VERSION 5.8 ;
BUSBITCHARS "[]" ;
DIVIDERCHAR "/" ;
UNITS
    DATABASE MICRONS 1000 ;
END UNITS

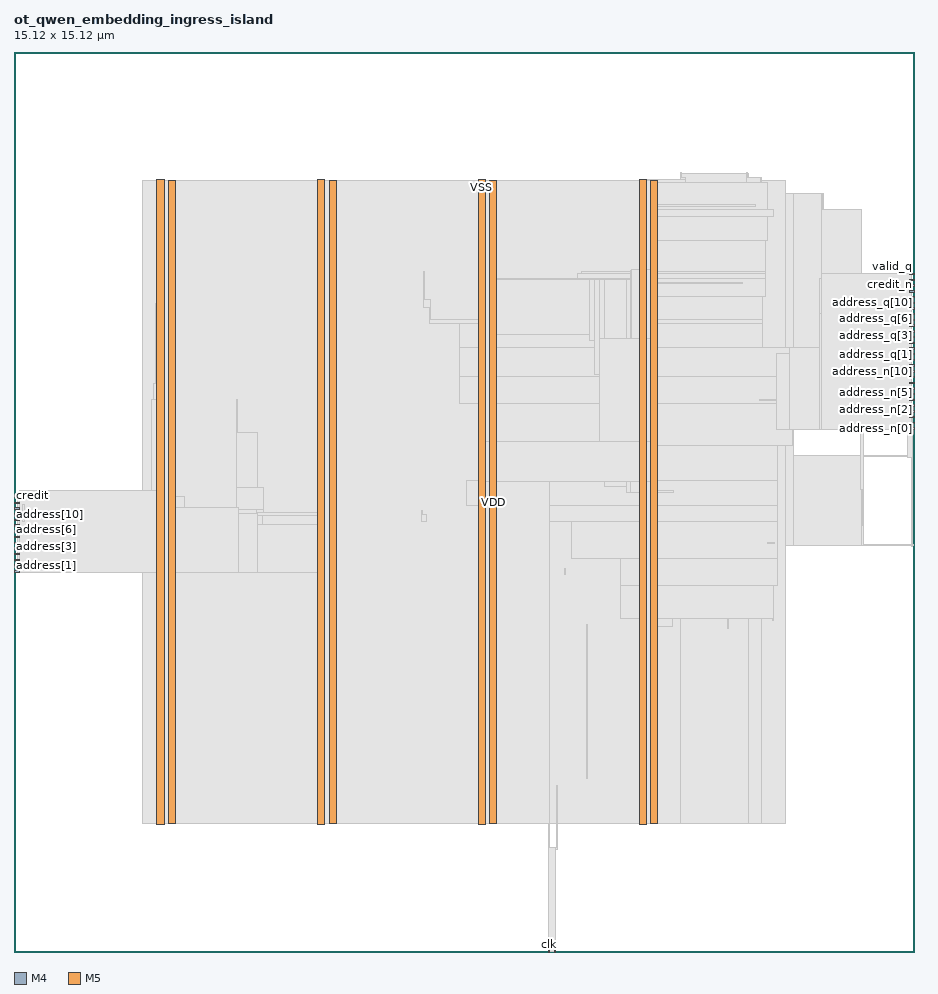
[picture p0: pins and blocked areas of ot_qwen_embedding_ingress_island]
MACRO ot_qwen_embedding_ingress_island
  FOREIGN ot_qwen_embedding_ingress_island 0 0 ;
  CLASS BLOCK ;
  SIZE 15.12 BY 15.12 ;
  PIN address[0]
    DIRECTION INPUT ;
    USE SIGNAL ;
    PORT
      LAYER M4 ;
        RECT  0 6.384 0.084 6.408 ;
    END
  END address[0]
  PIN address[10]
    DIRECTION INPUT ;
    USE SIGNAL ;
    PORT
      LAYER M4 ;
        RECT  0 7.344 0.084 7.368 ;
    END
  END address[10]
  PIN address[11]
    DIRECTION INPUT ;
    USE SIGNAL ;
    PORT
      LAYER M4 ;
        RECT  0 7.44 0.084 7.464 ;
    END
  END address[11]
  PIN address[1]
    DIRECTION INPUT ;
    USE SIGNAL ;
    PORT
      LAYER M4 ;
        RECT  0 6.48 0.084 6.504 ;
    END
  END address[1]
  PIN address[2]
    DIRECTION INPUT ;
    USE SIGNAL ;
    PORT
      LAYER M4 ;
        RECT  0 6.576 0.084 6.6 ;
    END
  END address[2]
  PIN address[3]
    DIRECTION INPUT ;
    USE SIGNAL ;
    PORT
      LAYER M4 ;
        RECT  0 6.672 0.084 6.696 ;
    END
  END address[3]
  PIN address[4]
    DIRECTION INPUT ;
    USE SIGNAL ;
    PORT
      LAYER M4 ;
        RECT  0 6.768 0.084 6.792 ;
    END
  END address[4]
  PIN address[5]
    DIRECTION INPUT ;
    USE SIGNAL ;
    PORT
      LAYER M4 ;
        RECT  0 6.864 0.084 6.888 ;
    END
  END address[5]
  PIN address[6]
    DIRECTION INPUT ;
    USE SIGNAL ;
    PORT
      LAYER M4 ;
        RECT  0 6.96 0.084 6.984 ;
    END
  END address[6]
  PIN address[7]
    DIRECTION INPUT ;
    USE SIGNAL ;
    PORT
      LAYER M4 ;
        RECT  0 7.056 0.084 7.08 ;
    END
  END address[7]
  PIN address[8]
    DIRECTION INPUT ;
    USE SIGNAL ;
    PORT
      LAYER M4 ;
        RECT  0 7.152 0.084 7.176 ;
    END
  END address[8]
  PIN address[9]
    DIRECTION INPUT ;
    USE SIGNAL ;
    PORT
      LAYER M4 ;
        RECT  0 7.248 0.084 7.272 ;
    END
  END address[9]
  PIN address_n[0]
    DIRECTION OUTPUT ;
    USE SIGNAL ;
    PORT
      LAYER M4 ;
        RECT  15.036 8.784 15.12 8.808 ;
    END
  END address_n[0]
  PIN address_n[10]
    DIRECTION OUTPUT ;
    USE SIGNAL ;
    PORT
      LAYER M4 ;
        RECT  15.036 9.744 15.12 9.768 ;
    END
  END address_n[10]
  PIN address_n[11]
    DIRECTION OUTPUT ;
    USE SIGNAL ;
    PORT
      LAYER M4 ;
        RECT  15.036 9.84 15.12 9.864 ;
    END
  END address_n[11]
  PIN address_n[1]
    DIRECTION OUTPUT ;
    USE SIGNAL ;
    PORT
      LAYER M4 ;
        RECT  15.036 8.88 15.12 8.904 ;
    END
  END address_n[1]
  PIN address_n[2]
    DIRECTION OUTPUT ;
    USE SIGNAL ;
    PORT
      LAYER M4 ;
        RECT  15.036 8.976 15.12 9 ;
    END
  END address_n[2]
  PIN address_n[3]
    DIRECTION OUTPUT ;
    USE SIGNAL ;
    PORT
      LAYER M4 ;
        RECT  15.036 9.072 15.12 9.096 ;
    END
  END address_n[3]
  PIN address_n[4]
    DIRECTION OUTPUT ;
    USE SIGNAL ;
    PORT
      LAYER M4 ;
        RECT  15.036 9.168 15.12 9.192 ;
    END
  END address_n[4]
  PIN address_n[5]
    DIRECTION OUTPUT ;
    USE SIGNAL ;
    PORT
      LAYER M4 ;
        RECT  15.036 9.264 15.12 9.288 ;
    END
  END address_n[5]
  PIN address_n[6]
    DIRECTION OUTPUT ;
    USE SIGNAL ;
    PORT
      LAYER M4 ;
        RECT  15.036 9.36 15.12 9.384 ;
    END
  END address_n[6]
  PIN address_n[7]
    DIRECTION OUTPUT ;
    USE SIGNAL ;
    PORT
      LAYER M4 ;
        RECT  15.036 9.456 15.12 9.48 ;
    END
  END address_n[7]
  PIN address_n[8]
    DIRECTION OUTPUT ;
    USE SIGNAL ;
    PORT
      LAYER M4 ;
        RECT  15.036 9.552 15.12 9.576 ;
    END
  END address_n[8]
  PIN address_n[9]
    DIRECTION OUTPUT ;
    USE SIGNAL ;
    PORT
      LAYER M4 ;
        RECT  15.036 9.648 15.12 9.672 ;
    END
  END address_n[9]
  PIN address_q[0]
    DIRECTION OUTPUT ;
    USE SIGNAL ;
    PORT
      LAYER M4 ;
        RECT  15.036 9.936 15.12 9.96 ;
    END
  END address_q[0]
  PIN address_q[10]
    DIRECTION OUTPUT ;
    USE SIGNAL ;
    PORT
      LAYER M4 ;
        RECT  15.036 10.896 15.12 10.92 ;
    END
  END address_q[10]
  PIN address_q[11]
    DIRECTION OUTPUT ;
    USE SIGNAL ;
    PORT
      LAYER M4 ;
        RECT  15.036 10.992 15.12 11.016 ;
    END
  END address_q[11]
  PIN address_q[1]
    DIRECTION OUTPUT ;
    USE SIGNAL ;
    PORT
      LAYER M4 ;
        RECT  15.036 10.032 15.12 10.056 ;
    END
  END address_q[1]
  PIN address_q[2]
    DIRECTION OUTPUT ;
    USE SIGNAL ;
    PORT
      LAYER M4 ;
        RECT  15.036 10.128 15.12 10.152 ;
    END
  END address_q[2]
  PIN address_q[3]
    DIRECTION OUTPUT ;
    USE SIGNAL ;
    PORT
      LAYER M4 ;
        RECT  15.036 10.224 15.12 10.248 ;
    END
  END address_q[3]
  PIN address_q[4]
    DIRECTION OUTPUT ;
    USE SIGNAL ;
    PORT
      LAYER M4 ;
        RECT  15.036 10.32 15.12 10.344 ;
    END
  END address_q[4]
  PIN address_q[5]
    DIRECTION OUTPUT ;
    USE SIGNAL ;
    PORT
      LAYER M4 ;
        RECT  15.036 10.416 15.12 10.44 ;
    END
  END address_q[5]
  PIN address_q[6]
    DIRECTION OUTPUT ;
    USE SIGNAL ;
    PORT
      LAYER M4 ;
        RECT  15.036 10.512 15.12 10.536 ;
    END
  END address_q[6]
  PIN address_q[7]
    DIRECTION OUTPUT ;
    USE SIGNAL ;
    PORT
      LAYER M4 ;
        RECT  15.036 10.608 15.12 10.632 ;
    END
  END address_q[7]
  PIN address_q[8]
    DIRECTION OUTPUT ;
    USE SIGNAL ;
    PORT
      LAYER M4 ;
        RECT  15.036 10.704 15.12 10.728 ;
    END
  END address_q[8]
  PIN address_q[9]
    DIRECTION OUTPUT ;
    USE SIGNAL ;
    PORT
      LAYER M4 ;
        RECT  15.036 10.8 15.12 10.824 ;
    END
  END address_q[9]
  PIN clk
    DIRECTION INPUT ;
    USE SIGNAL ;
    PORT
      LAYER M5 ;
        RECT  8.976 0 9 0.084 ;
    END
  END clk
  PIN credit
    DIRECTION INPUT ;
    USE SIGNAL ;
    PORT
      LAYER M4 ;
        RECT  0 7.536 0.084 7.56 ;
    END
  END credit
  PIN credit_n
    DIRECTION OUTPUT ;
    USE SIGNAL ;
    PORT
      LAYER M4 ;
        RECT  15.036 11.088 15.12 11.112 ;
    END
  END credit_n
  PIN credit_q
    DIRECTION OUTPUT ;
    USE SIGNAL ;
    PORT
      LAYER M4 ;
        RECT  15.036 11.184 15.12 11.208 ;
    END
  END credit_q
  PIN rst_n
    DIRECTION INPUT ;
    USE SIGNAL ;
    PORT
      LAYER M5 ;
        RECT  9.072 0 9.096 0.084 ;
    END
  END rst_n
  PIN valid
    DIRECTION INPUT ;
    USE SIGNAL ;
    PORT
      LAYER M4 ;
        RECT  0 7.632 0.084 7.656 ;
    END
  END valid
  PIN valid_n
    DIRECTION OUTPUT ;
    USE SIGNAL ;
    PORT
      LAYER M4 ;
        RECT  15.036 11.28 15.12 11.304 ;
    END
  END valid_n
  PIN valid_q
    DIRECTION OUTPUT ;
    USE SIGNAL ;
    PORT
      LAYER M4 ;
        RECT  15.036 11.376 15.12 11.4 ;
    END
  END valid_q
  PIN VDD
    DIRECTION INOUT ;
    USE POWER ;
    PORT
      LAYER M5 ;
        RECT  10.692 2.151 10.812 12.969 ;
        RECT  7.992 2.151 8.112 12.969 ;
        RECT  5.292 2.151 5.412 12.969 ;
        RECT  2.592 2.151 2.712 12.969 ;
    END
  END VDD
  PIN VSS
    DIRECTION INOUT ;
    USE GROUND ;
    PORT
      LAYER M5 ;
        RECT  10.5 2.137 10.62 12.983 ;
        RECT  7.8 2.137 7.92 12.983 ;
        RECT  5.1 2.137 5.22 12.983 ;
        RECT  2.4 2.137 2.52 12.983 ;
    END
  END VSS
  OBS
    LAYER RVTN ;
     RECT  2.16 2.16 12.96 2.295 ;
     RECT  2.16 2.565 12.96 2.835 ;
     RECT  2.16 3.105 12.96 3.375 ;
     RECT  2.16 3.645 12.96 3.915 ;
     RECT  2.16 4.185 12.96 4.455 ;
     RECT  2.16 4.725 12.96 4.995 ;
     RECT  2.16 5.265 12.96 5.535 ;
     RECT  2.16 5.805 12.96 6.075 ;
     RECT  2.16 6.345 12.96 6.615 ;
     RECT  2.16 6.885 12.96 7.155 ;
     RECT  2.16 7.425 12.96 7.695 ;
     RECT  2.16 7.965 12.96 8.235 ;
     RECT  2.16 8.505 12.96 8.775 ;
     RECT  2.16 9.045 12.96 9.315 ;
     RECT  2.16 9.585 12.96 9.855 ;
     RECT  2.16 10.125 12.96 10.395 ;
     RECT  2.16 10.665 12.96 10.935 ;
     RECT  2.16 11.205 12.96 11.475 ;
     RECT  2.16 11.745 12.96 12.015 ;
     RECT  2.16 12.285 12.96 12.555 ;
     RECT  2.16 12.825 12.96 12.96 ;
    LAYER RVTP ;
     RECT  2.16 2.295 12.96 2.565 ;
     RECT  2.16 2.835 12.96 3.105 ;
     RECT  2.16 3.375 12.96 3.645 ;
     RECT  2.16 3.915 12.96 4.185 ;
     RECT  2.16 4.455 12.96 4.725 ;
     RECT  2.16 4.995 12.96 5.265 ;
     RECT  2.16 5.535 12.96 5.805 ;
     RECT  2.16 6.075 12.96 6.345 ;
     RECT  2.16 6.615 12.96 6.885 ;
     RECT  2.16 7.155 12.96 7.425 ;
     RECT  2.16 7.695 12.96 7.965 ;
     RECT  2.16 8.235 12.96 8.505 ;
     RECT  2.16 8.775 12.96 9.045 ;
     RECT  2.16 9.315 12.96 9.585 ;
     RECT  2.16 9.855 12.96 10.125 ;
     RECT  2.16 10.395 12.96 10.665 ;
     RECT  2.16 10.935 12.96 11.205 ;
     RECT  2.16 11.475 12.96 11.745 ;
     RECT  2.16 12.015 12.96 12.285 ;
     RECT  2.16 12.555 12.96 12.825 ;
    LAYER M1 ;
     RECT  2.16 2.151 12.96 12.969 ;
    LAYER M2 ;
     RECT  2.16 2.151 11.191 12.969 ;
     RECT  11.191 2.151 12.335 13.086 ;
     RECT  12.335 2.151 12.551 13.014 ;
     RECT  12.551 2.151 12.96 12.969 ;
     RECT  12.96 6.822 13.091 12.744 ;
     RECT  13.091 9.09 13.595 12.744 ;
     RECT  13.595 9.09 14.171 12.474 ;
     RECT  14.171 9.09 14.207 10.926 ;
     RECT  14.171 12.186 14.207 12.474 ;
     RECT  13.091 6.822 14.243 8.334 ;
     RECT  14.207 9.36 14.243 10.926 ;
     RECT  14.207 12.456 14.243 12.474 ;
     RECT  14.243 6.822 14.279 7.182 ;
     RECT  14.243 8.316 15.035 8.334 ;
     RECT  14.279 6.822 15.107 6.84 ;
     RECT  15.007 9.171 15.107 9.189 ;
    LAYER M3 ;
     RECT  2.415 2.143 2.505 2.413 ;
     RECT  5.115 2.143 5.205 2.413 ;
     RECT  7.815 2.143 7.905 2.413 ;
     RECT  10.515 2.143 10.605 2.413 ;
     RECT  9.108 1.723 9.126 2.795 ;
     RECT  10.515 2.413 10.797 5.467 ;
     RECT  9.612 2.911 9.63 5.495 ;
     RECT  10.515 5.467 11.07 5.611 ;
     RECT  11.988 5.431 12.006 5.611 ;
     RECT  12.744 5.575 12.762 5.611 ;
     RECT  10.188 5.611 12.762 6.151 ;
     RECT  5.115 2.413 5.397 6.379 ;
     RECT  9.252 6.349 9.27 6.449 ;
     RECT  2.415 2.413 2.697 6.475 ;
     RECT  4.68 6.379 5.397 6.571 ;
     RECT  10.188 6.151 12.834 6.619 ;
     RECT  4.572 6.571 5.397 6.667 ;
     RECT  7.815 2.413 8.097 7.159 ;
     RECT  7.815 7.159 8.298 7.231 ;
     RECT  9.36 6.619 12.834 7.231 ;
     RECT  2.304 6.475 2.697 7.321 ;
     RECT  4.176 6.667 5.397 7.339 ;
     RECT  6.84 7.231 6.93 7.349 ;
     RECT  4.068 7.339 5.397 7.385 ;
     RECT  6.84 7.349 6.858 7.421 ;
     RECT  4.068 7.385 4.194 7.435 ;
     RECT  7.815 7.231 12.834 7.501 ;
     RECT  0.324 7.531 0.342 7.627 ;
     RECT  2.304 7.321 2.862 7.655 ;
     RECT  0.108 7.627 0.342 7.661 ;
     RECT  0.108 7.661 0.126 7.757 ;
     RECT  14.256 7.159 14.274 7.771 ;
     RECT  3.744 7.435 4.194 7.799 ;
     RECT  7.596 7.501 12.834 7.925 ;
     RECT  15.084 6.817 15.102 8.311 ;
     RECT  7.815 7.925 12.834 8.509 ;
     RECT  3.744 7.799 4.086 8.735 ;
     RECT  14.22 7.771 14.274 9.005 ;
     RECT  14.22 9.005 14.238 9.085 ;
     RECT  15.012 8.311 15.102 9.194 ;
     RECT  15.012 9.194 15.03 9.197 ;
     RECT  7.815 8.509 13.086 9.211 ;
     RECT  2.304 7.655 2.697 9.275 ;
     RECT  3.744 8.735 3.762 9.275 ;
     RECT  2.34 9.275 2.697 9.545 ;
     RECT  7.488 9.211 13.086 9.661 ;
     RECT  14.184 9.085 14.238 9.661 ;
     RECT  7.488 9.661 14.238 10.157 ;
     RECT  7.488 10.157 12.582 10.561 ;
     RECT  6.984 10.561 12.582 10.625 ;
     RECT  6.984 10.625 7.002 10.831 ;
     RECT  2.376 9.545 2.697 10.895 ;
     RECT  6.876 10.831 7.002 10.967 ;
     RECT  7.815 10.625 12.582 11.011 ;
     RECT  13.536 10.157 14.238 11.309 ;
     RECT  7.815 11.011 12.618 11.315 ;
     RECT  9.468 11.315 12.618 11.399 ;
     RECT  6.876 10.967 6.894 11.435 ;
     RECT  9.54 11.399 12.618 11.435 ;
     RECT  10.515 11.435 12.618 11.947 ;
     RECT  10.515 11.947 12.654 12.361 ;
     RECT  10.515 12.361 12.762 12.479 ;
     RECT  13.572 11.309 14.238 12.479 ;
     RECT  2.415 10.895 2.697 12.707 ;
     RECT  5.115 7.385 5.397 12.707 ;
     RECT  7.815 11.315 8.097 12.707 ;
     RECT  13.572 12.479 13.59 12.749 ;
     RECT  10.515 12.479 12.654 12.929 ;
     RECT  2.415 12.707 2.505 12.977 ;
     RECT  5.115 12.707 5.205 12.977 ;
     RECT  7.815 12.707 7.905 12.977 ;
     RECT  10.515 12.929 11.286 12.977 ;
     RECT  11.196 12.977 11.286 13.019 ;
     RECT  12.312 12.929 12.546 13.019 ;
     RECT  11.196 13.019 11.214 13.091 ;
     RECT  12.312 13.019 12.33 13.091 ;
    LAYER M4 ;
     RECT  0.06 6.384 0.097 7.656 ;
     RECT  0.097 6.384 2.408 7.752 ;
     RECT  2.408 2.148 2.512 12.972 ;
     RECT  2.512 2.418 2.704 12.702 ;
     RECT  2.704 6.384 3.773 7.464 ;
     RECT  3.773 6.384 4.097 7.368 ;
     RECT  4.097 6.384 5.108 7.176 ;
     RECT  5.108 2.148 5.212 12.972 ;
     RECT  5.212 2.418 5.404 12.702 ;
     RECT  7.808 2.148 7.912 12.972 ;
     RECT  7.912 2.418 8.104 12.702 ;
     RECT  9.053 1.728 9.137 1.752 ;
     RECT  8.104 10.368 9.673 11.304 ;
     RECT  9.673 10.272 9.745 11.304 ;
     RECT  8.104 7.968 9.829 8.568 ;
     RECT  9.745 9.696 9.829 11.304 ;
     RECT  9.829 7.92 9.925 11.304 ;
     RECT  9.925 7.824 10.285 11.304 ;
     RECT  10.285 7.728 10.357 11.304 ;
     RECT  10.357 7.728 10.508 11.448 ;
     RECT  10.508 2.148 10.612 12.972 ;
     RECT  10.612 2.418 10.804 12.702 ;
     RECT  10.804 7.728 11.081 7.752 ;
     RECT  10.804 11.232 12.233 11.256 ;
     RECT  10.804 12.528 12.449 12.552 ;
     RECT  12.661 6.864 12.773 6.888 ;
     RECT  12.517 9.264 12.805 9.288 ;
     RECT  12.805 8.784 13.021 10.056 ;
     RECT  13.021 8.784 13.525 10.152 ;
     RECT  13.525 8.784 13.561 10.728 ;
     RECT  13.561 8.784 15.084 11.4 ;
    LAYER M5 ;
     RECT  8.976 0.016 9.096 1.763 ;
     RECT  2.4 2.137 2.52 2.151 ;
     RECT  5.1 2.137 5.22 2.151 ;
     RECT  7.8 2.137 7.92 2.151 ;
     RECT  8.976 1.763 9 2.151 ;
     RECT  10.5 2.137 10.62 2.151 ;
     RECT  0.144 7.237 0.168 7.523 ;
     RECT  7.8 2.151 9 7.909 ;
     RECT  10.5 2.151 10.812 7.909 ;
     RECT  7.8 7.909 10.812 8.579 ;
     RECT  9.84 8.579 10.812 10.307 ;
     RECT  10.368 10.307 10.812 11.459 ;
     RECT  2.4 2.151 2.712 12.969 ;
     RECT  5.1 2.151 5.412 12.969 ;
     RECT  7.8 8.579 8.112 12.969 ;
     RECT  10.5 11.459 10.812 12.969 ;
     RECT  2.4 12.969 2.52 12.983 ;
     RECT  5.1 12.969 5.22 12.983 ;
     RECT  7.8 12.969 7.92 12.983 ;
     RECT  10.5 12.969 10.62 12.983 ;
  END
END ot_qwen_embedding_ingress_island
END LIBRARY
